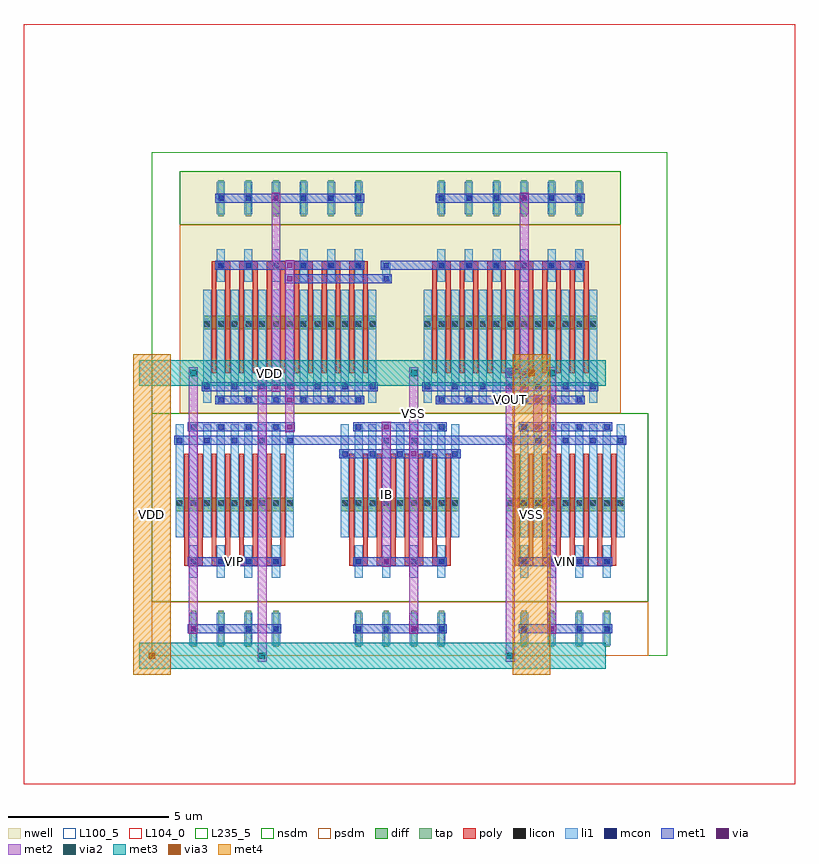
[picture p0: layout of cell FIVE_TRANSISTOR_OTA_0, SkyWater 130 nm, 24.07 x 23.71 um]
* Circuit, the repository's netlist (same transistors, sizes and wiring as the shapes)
* NGSPICE file created from FIVE_TRANSISTOR_OTA_0.ext - technology: sky130A

.subckt PMOS_S_21674997_X6_Y1_1774868989 a_200_252# w_0_0# a_230_525#
X0 w_0_0# a_200_252# a_230_525# w_0_0# sky130_fd_pr__pfet_01v8 ad=0.1113 pd=1.37 as=0.0588 ps=0.7 w=0.42 l=0.15 M=12
.ends

.subckt DCL_PMOS_S_80097108_X6_Y1_1774868987 a_200_252# w_0_0#
X0 w_0_0# a_200_252# a_200_252# w_0_0# sky130_fd_pr__pfet_01v8 ad=0.1113 pd=1.37 as=0.0588 ps=0.7 w=0.42 l=0.15 M=12
.ends

.subckt NMOS_4T_66219913_X4_Y1_1774868988 a_147_525# a_200_252# a_241_1232# a_230_525#
X0 a_230_525# a_200_252# a_147_525# a_241_1232# sky130_fd_pr__nfet_01v8 ad=0.0588 pd=0.7 as=0.0588 ps=0.7 w=0.42 l=0.15 M=8
.ends

.subckt SCM_NMOS_79747830_X2_Y1_1774868990 a_402_525# a_147_525# a_200_252#
X0 a_402_525# a_200_252# a_147_525# a_147_525# sky130_fd_pr__nfet_01v8 ad=0.0588 pd=0.7 as=0.0588 ps=0.7 w=0.42 l=0.15 M=4
X1 a_200_252# a_200_252# a_147_525# a_147_525# sky130_fd_pr__nfet_01v8 ad=0.0588 pd=0.7 as=0.0588 ps=0.7 w=0.42 l=0.15 M=4
.ends

.subckt FIVE_TRANSISTOR_OTA_0 IB VOUT VIP VIN VSS VDD
XPMOS_S_21674997_X6_Y1_1774868989_0 m1_774_1400# VDD VOUT PMOS_S_21674997_X6_Y1_1774868989
XDCL_PMOS_S_80097108_X6_Y1_1774868987_0 m1_774_1400# VDD DCL_PMOS_S_80097108_X6_Y1_1774868987
XNMOS_4T_66219913_X4_Y1_1774868988_0 m1_860_1316# VIN VSS VOUT NMOS_4T_66219913_X4_Y1_1774868988
XNMOS_4T_66219913_X4_Y1_1774868988_1 m1_860_1316# VIP VSS m1_774_1400# NMOS_4T_66219913_X4_Y1_1774868988
XSCM_NMOS_79747830_X2_Y1_1774868990_0 m1_860_1316# VSS IB SCM_NMOS_79747830_X2_Y1_1774868990
.ends

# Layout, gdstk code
from math import pi, radians
import gdstk
lib = gdstk.Library(unit=1e-6, precision=1e-09)
def R(c, l, rs):  # rectangles x0, y0, x1, y1
    for r in rs: c.add(gdstk.rectangle(r[:2], r[2:], *l))
def A(c, l, x, y, w, h, nx, ny, dx, dy):  # array of equal rectangles
    R(c, l, [(x+i*dx, y+j*dy, x+i*dx+w, y+j*dy+h) for i in range(nx) for j in range(ny)])
def P(c, l, *ps):  # polygons
    for p in ps: c.add(gdstk.Polygon(p, *l))
nwell = (64, 20)
diff = (65, 20)
tap = (65, 44)
poly = (66, 20)
licon = (66, 44)
li1 = (67, 20)
mcon = (67, 44)
met1 = (68, 20)
via = (68, 44)
met2 = (69, 20)
via2 = (69, 44)
met3 = (70, 20)
via3 = (70, 44)
met4 = (71, 20)
nsdm = (93, 44)
psdm = (94, 20)
L100_5 = (100, 5)
L104_0 = (104, 0)
L235_5 = (235, 5)

scm_nmos_79747830_x2_y1_ = lib.new_cell('SCM_NMOS_79747830_X2_Y1_1774868990')
R(scm_nmos_79747830_x2_y1_, diff, [(0.735,2.625,4.425,3.045)])
A(scm_nmos_79747830_x2_y1_, tap, 1.205, 6.16, 0.17, 1.12, 4, 1, 0.86, 0)
A(scm_nmos_79747830_x2_y1_, poly, 1, 1.26, 0.15, 3.36, 8, 1, 0.43, 0)
A(scm_nmos_79747830_x2_y1_, poly, 1, 4.485, 0.58, 0.27, 4, 1, 0.86, 0)
A(scm_nmos_79747830_x2_y1_, licon, 0.775, 2.705, 0.17, 0.17, 3, 1, 0.43, 0)
A(scm_nmos_79747830_x2_y1_, licon, 1.635, 2.705, 0.17, 0.17, 3, 1, 0.43, 0)
A(scm_nmos_79747830_x2_y1_, licon, 2.495, 2.705, 0.17, 0.17, 3, 1, 0.43, 0)
A(scm_nmos_79747830_x2_y1_, licon, 3.355, 2.705, 0.17, 0.17, 3, 1, 0.43, 0)
A(scm_nmos_79747830_x2_y1_, licon, 1.205, 4.535, 0.17, 0.17, 4, 2, 0.86, 2.1)
A(scm_nmos_79747830_x2_y1_, li1, 0.735, 0.335, 0.25, 3.53, 9, 1, 0.43, 0)
A(scm_nmos_79747830_x2_y1_, li1, 1.165, 4.115, 0.25, 1.01, 4, 2, 0.86, 2.1)
A(scm_nmos_79747830_x2_y1_, mcon, 0.775, 1.175, 0.17, 0.17, 5, 1, 0.86, 0)
A(scm_nmos_79747830_x2_y1_, mcon, 1.205, 4.535, 0.17, 0.17, 4, 2, 0.86, 2.1)
R(scm_nmos_79747830_x2_y1_, mcon, [(1.205,0.335,1.375,0.505), (3.785,0.335,3.955,0.505), (2.065,0.755,2.235,0.925), (2.925,0.755,3.095,0.925)])
R(scm_nmos_79747830_x2_y1_, met1, [(1.12,0.28,4.04,0.56), (1.98,0.7,3.18,0.98), (0.69,1.12,4.47,1.4), (1.12,4.48,4.04,4.76), (1.12,6.58,4.04,6.86)])
R(scm_nmos_79747830_x2_y1_, via, [(2.075,0.345,2.225,0.495), (2.935,1.185,3.085,1.335), (2.075,4.545,2.225,4.695), (2.935,6.645,3.085,6.795)])
R(scm_nmos_79747830_x2_y1_, met2, [(2.01,0.26,2.29,4.78), (2.87,1.1,3.15,6.88)])
R(scm_nmos_79747830_x2_y1_, nsdm, [(0,0,5.16,5.88)])
R(scm_nmos_79747830_x2_y1_, psdm, [(0,5.88,5.16,7.56)])
R(scm_nmos_79747830_x2_y1_, L100_5, [(0,0,5.16,7.56)])

dcl_pmos_s_80097108_x6_y = lib.new_cell('DCL_PMOS_S_80097108_X6_Y1_1774868987')
R(dcl_pmos_s_80097108_x6_y, nwell, [(0,0,6.88,7.56)])
R(dcl_pmos_s_80097108_x6_y, diff, [(0.735,2.625,6.145,3.045)])
A(dcl_pmos_s_80097108_x6_y, tap, 1.205, 6.16, 0.17, 1.12, 6, 1, 0.86, 0)
A(dcl_pmos_s_80097108_x6_y, poly, 1, 1.26, 0.15, 3.36, 12, 1, 0.43, 0)
A(dcl_pmos_s_80097108_x6_y, poly, 1, 4.485, 0.58, 0.27, 6, 1, 0.86, 0)
A(dcl_pmos_s_80097108_x6_y, licon, 0.775, 2.705, 0.17, 0.17, 3, 1, 0.43, 0)
A(dcl_pmos_s_80097108_x6_y, licon, 1.635, 2.705, 0.17, 0.17, 3, 1, 0.43, 0)
A(dcl_pmos_s_80097108_x6_y, licon, 2.495, 2.705, 0.17, 0.17, 3, 1, 0.43, 0)
A(dcl_pmos_s_80097108_x6_y, licon, 3.355, 2.705, 0.17, 0.17, 3, 1, 0.43, 0)
A(dcl_pmos_s_80097108_x6_y, licon, 4.215, 2.705, 0.17, 0.17, 3, 1, 0.43, 0)
A(dcl_pmos_s_80097108_x6_y, licon, 5.075, 2.705, 0.17, 0.17, 3, 1, 0.43, 0)
A(dcl_pmos_s_80097108_x6_y, licon, 1.205, 4.535, 0.17, 0.17, 6, 2, 0.86, 2.1)
A(dcl_pmos_s_80097108_x6_y, li1, 0.735, 0.335, 0.25, 3.53, 13, 1, 0.43, 0)
A(dcl_pmos_s_80097108_x6_y, li1, 1.165, 4.115, 0.25, 1.01, 6, 2, 0.86, 2.1)
A(dcl_pmos_s_80097108_x6_y, mcon, 1.205, 0.335, 0.17, 0.17, 6, 2, 0.86, 4.2)
A(dcl_pmos_s_80097108_x6_y, mcon, 0.775, 0.755, 0.17, 0.17, 7, 1, 0.86, 0)
A(dcl_pmos_s_80097108_x6_y, mcon, 1.205, 6.635, 0.17, 0.17, 6, 1, 0.86, 0)
R(dcl_pmos_s_80097108_x6_y, met1, [(1.12,0.28,5.76,0.56), (0.69,0.7,6.19,0.98), (1.12,4.48,5.76,4.76), (1.12,6.58,5.76,6.86)])
R(dcl_pmos_s_80097108_x6_y, via, [(3.365,0.345,3.515,0.495), (3.795,0.765,3.945,0.915), (3.365,4.545,3.515,4.695), (3.795,6.645,3.945,6.795)])
R(dcl_pmos_s_80097108_x6_y, met2, [(3.3,0.26,3.58,4.78), (3.73,0.68,4.01,6.88)])
R(dcl_pmos_s_80097108_x6_y, nsdm, [(0,5.88,6.88,7.56)])
R(dcl_pmos_s_80097108_x6_y, psdm, [(0,0,6.88,5.88)])
R(dcl_pmos_s_80097108_x6_y, L100_5, [(0,0,6.88,7.56)])

pmos_s_21674997_x6_y1_17 = lib.new_cell('PMOS_S_21674997_X6_Y1_1774868989')
R(pmos_s_21674997_x6_y1_17, nwell, [(0,0,6.88,7.56)])
R(pmos_s_21674997_x6_y1_17, diff, [(0.735,2.625,6.145,3.045)])
A(pmos_s_21674997_x6_y1_17, tap, 1.205, 6.16, 0.17, 1.12, 6, 1, 0.86, 0)
A(pmos_s_21674997_x6_y1_17, poly, 1, 1.26, 0.15, 3.36, 12, 1, 0.43, 0)
A(pmos_s_21674997_x6_y1_17, poly, 1, 4.485, 0.58, 0.27, 6, 1, 0.86, 0)
A(pmos_s_21674997_x6_y1_17, licon, 0.775, 2.705, 0.17, 0.17, 3, 1, 0.43, 0)
A(pmos_s_21674997_x6_y1_17, licon, 1.635, 2.705, 0.17, 0.17, 3, 1, 0.43, 0)
A(pmos_s_21674997_x6_y1_17, licon, 2.495, 2.705, 0.17, 0.17, 3, 1, 0.43, 0)
A(pmos_s_21674997_x6_y1_17, licon, 3.355, 2.705, 0.17, 0.17, 3, 1, 0.43, 0)
A(pmos_s_21674997_x6_y1_17, licon, 4.215, 2.705, 0.17, 0.17, 3, 1, 0.43, 0)
A(pmos_s_21674997_x6_y1_17, licon, 5.075, 2.705, 0.17, 0.17, 3, 1, 0.43, 0)
A(pmos_s_21674997_x6_y1_17, licon, 1.205, 4.535, 0.17, 0.17, 6, 2, 0.86, 2.1)
A(pmos_s_21674997_x6_y1_17, li1, 0.735, 0.335, 0.25, 3.53, 13, 1, 0.43, 0)
A(pmos_s_21674997_x6_y1_17, li1, 1.165, 4.115, 0.25, 1.01, 6, 2, 0.86, 2.1)
A(pmos_s_21674997_x6_y1_17, mcon, 1.205, 0.335, 0.17, 0.17, 6, 2, 0.86, 4.2)
A(pmos_s_21674997_x6_y1_17, mcon, 0.775, 0.755, 0.17, 0.17, 7, 1, 0.86, 0)
A(pmos_s_21674997_x6_y1_17, mcon, 1.205, 6.635, 0.17, 0.17, 6, 1, 0.86, 0)
R(pmos_s_21674997_x6_y1_17, met1, [(1.12,0.28,5.76,0.56), (0.69,0.7,6.19,0.98), (1.12,4.48,5.76,4.76), (1.12,6.58,5.76,6.86)])
R(pmos_s_21674997_x6_y1_17, via, [(3.795,0.765,3.945,0.915), (3.795,6.645,3.945,6.795)])
R(pmos_s_21674997_x6_y1_17, met2, [(3.73,0.68,4.01,6.88)])
R(pmos_s_21674997_x6_y1_17, nsdm, [(0,5.88,6.88,7.56)])
R(pmos_s_21674997_x6_y1_17, psdm, [(0,0,6.88,5.88)])
R(pmos_s_21674997_x6_y1_17, L100_5, [(0,0,6.88,7.56)])

nmos_4t_66219913_x4_y1_1 = lib.new_cell('NMOS_4T_66219913_X4_Y1_1774868988')
R(nmos_4t_66219913_x4_y1_1, diff, [(0.735,2.625,4.425,3.045)])
A(nmos_4t_66219913_x4_y1_1, tap, 1.205, 6.16, 0.17, 1.12, 4, 1, 0.86, 0)
A(nmos_4t_66219913_x4_y1_1, poly, 1, 1.26, 0.15, 3.36, 8, 1, 0.43, 0)
A(nmos_4t_66219913_x4_y1_1, poly, 1, 4.485, 0.58, 0.27, 4, 1, 0.86, 0)
A(nmos_4t_66219913_x4_y1_1, licon, 0.775, 2.705, 0.17, 0.17, 3, 1, 0.43, 0)
A(nmos_4t_66219913_x4_y1_1, licon, 1.635, 2.705, 0.17, 0.17, 3, 1, 0.43, 0)
A(nmos_4t_66219913_x4_y1_1, licon, 2.495, 2.705, 0.17, 0.17, 3, 1, 0.43, 0)
A(nmos_4t_66219913_x4_y1_1, licon, 3.355, 2.705, 0.17, 0.17, 3, 1, 0.43, 0)
A(nmos_4t_66219913_x4_y1_1, licon, 1.205, 4.535, 0.17, 0.17, 4, 2, 0.86, 2.1)
A(nmos_4t_66219913_x4_y1_1, li1, 0.735, 0.335, 0.25, 3.53, 9, 1, 0.43, 0)
A(nmos_4t_66219913_x4_y1_1, li1, 1.165, 4.115, 0.25, 1.01, 4, 2, 0.86, 2.1)
A(nmos_4t_66219913_x4_y1_1, mcon, 1.205, 0.335, 0.17, 0.17, 4, 2, 0.86, 4.2)
A(nmos_4t_66219913_x4_y1_1, mcon, 0.775, 0.755, 0.17, 0.17, 5, 1, 0.86, 0)
A(nmos_4t_66219913_x4_y1_1, mcon, 1.205, 6.635, 0.17, 0.17, 4, 1, 0.86, 0)
R(nmos_4t_66219913_x4_y1_1, met1, [(1.12,0.28,4.04,0.56), (0.69,0.7,4.47,0.98), (1.12,4.48,4.04,4.76), (1.12,6.58,4.04,6.86)])
R(nmos_4t_66219913_x4_y1_1, nsdm, [(0,0,5.16,5.88)])
R(nmos_4t_66219913_x4_y1_1, psdm, [(0,5.88,5.16,7.56)])
R(nmos_4t_66219913_x4_y1_1, L100_5, [(0,0,5.16,7.56)])

five_transistor_ota_0 = lib.new_cell('FIVE_TRANSISTOR_OTA_0')
R(five_transistor_ota_0, li1, [(7.185,11.675,7.435,11.845), (7.185,11.675,7.435,11.845), (7.185,11.76,7.435,12.18), (7.185,12.095,7.435,12.265), (7.185,12.095,7.435,12.265)])
R(five_transistor_ota_0, mcon, [(7.225,11.675,7.395,11.845), (7.225,11.675,7.395,11.845), (7.225,12.095,7.395,12.265), (7.225,12.095,7.395,12.265)])
R(five_transistor_ota_0, met1, [(1.13,0.7,1.45,0.98), (1.13,0.7,1.45,0.98), (1.13,0.7,1.45,0.98), (12.31,0.7,12.63,0.98), (12.31,0.7,12.63,0.98), (4.3,6.58,7.31,6.86), (8.17,6.58,11.18,6.86), (3.87,7,4.3,7.28), (4.14,7,4.46,7.28), (4.14,7,4.46,7.28), (4.14,7,4.46,7.28), (4.14,7,4.46,7.28), (11.88,7,12.2,7.28), (11.88,7,12.2,7.28), (11.88,7.84,12.2,8.12), (11.88,7.84,12.2,8.12), (3.28,8.68,3.6,8.96), (3.28,8.68,3.6,8.96), (3.28,8.68,3.6,8.96), (3.44,8.68,3.87,8.96), (3.71,8.68,4.03,8.96), (3.71,8.68,4.03,8.96), (3.71,8.68,4.03,8.96), (11.02,8.68,11.34,8.96), (11.02,8.68,11.34,8.96), (11.18,8.68,11.61,8.96), (11.45,8.68,11.77,8.96), (11.45,8.68,11.77,8.96), (4.14,11.62,4.46,11.9), (4.14,11.62,4.46,11.9), (4.3,11.62,7.31,11.9), (7.14,11.62,7.48,11.9), (7.14,11.62,7.48,11.9), (7.14,12.04,7.48,12.32), (7.14,12.04,7.48,12.32), (7.31,12.04,9.03,12.32)])
P(five_transistor_ota_0, met1, [(0,0),(0,0),(0,0),(0,0)],
  [(0,0),(0,0),(0,0),(0,0)],
  [(0,0),(0,0),(0,0),(0,0)],
  [(0,0),(0,0),(0,0),(0,0)],
  [(0,0),(0,0),(0,0),(0,0)],
  [(0,0),(0,0),(0,0),(0,0)],
  [(0,0),(0,0),(0,0),(0,0)],
  [(0,0),(0,0),(0,0),(0,0)],
  [(0,0),(0,0),(0,0),(0,0)],
  [(0,0),(0,0),(0,0),(0,0)],
  [(0,0),(0,0),(0,0),(0,0)],
  [(0,0),(0,0),(0,0),(0,0)],
  [(0,0),(0,0),(0,0),(0,0)],
  [(0,0),(0,0),(0,0),(0,0)])
R(five_transistor_ota_0, via, [(1.215,0.765,1.365,0.915), (1.215,0.765,1.365,0.915), (1.215,0.765,1.365,0.915), (12.395,0.765,12.545,0.915), (12.395,0.765,12.545,0.915), (4.225,7.065,4.375,7.215), (4.225,7.065,4.375,7.215), (4.225,7.065,4.375,7.215), (4.225,7.065,4.375,7.215), (11.965,7.065,12.115,7.215), (11.965,7.065,12.115,7.215), (11.965,7.905,12.115,8.055), (11.965,7.905,12.115,8.055), (3.365,8.745,3.515,8.895), (3.365,8.745,3.515,8.895), (3.365,8.745,3.515,8.895), (3.795,8.745,3.945,8.895), (3.795,8.745,3.945,8.895), (3.795,8.745,3.945,8.895), (11.105,8.745,11.255,8.895), (11.105,8.745,11.255,8.895), (11.535,8.745,11.685,8.895), (11.535,8.745,11.685,8.895), (4.225,11.685,4.375,11.835), (4.225,11.685,4.375,11.835)])
R(five_transistor_ota_0, met2, [(3.3,-0.185,3.58,0.185), (3.3,-0.185,3.58,0.185), (3.3,-0.185,3.58,0.185), (11.04,-0.185,11.32,0.185), (11.04,-0.185,11.32,0.185), (3.3,0,3.58,8.82), (11.04,0,11.32,8.82), (1.15,0.68,1.43,1), (1.15,0.68,1.43,1), (1.15,0.68,1.43,1), (12.33,0.68,12.61,1), (12.33,0.68,12.61,1), (1.15,0.84,1.43,8.82), (12.33,0.84,12.61,8.82), (8.03,6.3,8.31,8.82), (4.16,6.98,4.44,7.3), (4.16,6.98,4.44,7.3), (4.16,6.98,4.44,7.3), (4.16,6.98,4.44,7.3), (11.9,6.98,12.18,7.3), (11.9,6.98,12.18,7.3), (4.16,7.14,4.44,7.98), (11.9,7.14,12.18,7.98), (11.9,7.82,12.18,8.14), (11.9,7.82,12.18,8.14), (1.15,8.635,1.43,9.005), (1.15,8.635,1.43,9.005), (1.15,8.635,1.43,9.005), (8.03,8.635,8.31,9.005), (8.03,8.635,8.31,9.005), (8.03,8.635,8.31,9.005), (8.03,8.635,8.31,9.005), (12.33,8.635,12.61,9.005), (12.33,8.635,12.61,9.005), (3.3,8.66,3.58,8.98), (3.3,8.66,3.58,8.98), (3.3,8.66,3.58,8.98), (3.73,8.66,4.01,8.98), (3.73,8.66,4.01,8.98), (3.73,8.66,4.01,8.98), (11.04,8.66,11.32,8.98), (11.04,8.66,11.32,8.98), (11.47,8.66,11.75,8.98), (11.47,8.66,11.75,8.98), (4.16,11.6,4.44,11.92), (4.16,11.6,4.44,11.92)])
P(five_transistor_ota_0, met2, [(0,0),(0,0),(0,0),(0,0)],
  [(0,0),(0,0),(0,0),(0,0)],
  [(0,0),(0,0),(0,0),(0,0)],
  [(0,0),(0,0),(0,0),(0,0)],
  [(0,0),(0,0),(0,0),(0,0)],
  [(0,0),(0,0),(0,0),(0,0)])
R(five_transistor_ota_0, via2, [(3.34,-0.1,3.54,0.1), (3.34,-0.1,3.54,0.1), (3.34,-0.1,3.54,0.1), (11.08,-0.1,11.28,0.1), (11.08,-0.1,11.28,0.1), (1.19,8.72,1.39,8.92), (1.19,8.72,1.39,8.92), (1.19,8.72,1.39,8.92), (8.07,8.72,8.27,8.92), (8.07,8.72,8.27,8.92), (8.07,8.72,8.27,8.92), (8.07,8.72,8.27,8.92), (12.37,8.72,12.57,8.92), (12.37,8.72,12.57,8.92)])
A(five_transistor_ota_0, met3, -0.4, -0.4, 4.24, 0.8, 3, 2, 3.44, 8.82)
R(five_transistor_ota_0, met3, [(-0.165,-0.4,0.165,0.4), (3.275,-0.4,3.605,0.4), (3.275,-0.4,3.605,0.4), (3.275,-0.4,3.605,0.4), (9.92,-0.4,12.24,0.4), (11.015,-0.4,11.345,0.4), (11.015,-0.4,11.345,0.4), (11.44,-0.4,14.16,0.4), (1.125,8.42,1.455,9.22), (1.125,8.42,1.455,9.22), (1.125,8.42,1.455,9.22), (8.005,8.42,8.335,9.22), (8.005,8.42,8.335,9.22), (8.005,8.42,8.335,9.22), (8.005,8.42,8.335,9.22), (9.92,8.42,12.24,9.22), (11.44,8.42,14.16,9.22), (11.675,8.42,12.005,9.22), (12.305,8.42,12.635,9.22), (12.305,8.42,12.635,9.22)])
R(five_transistor_ota_0, via3, [(-0.1,-0.1,0.1,0.1), (11.74,8.72,11.94,8.92)])
R(five_transistor_ota_0, met4, [(-0.59,-0.59,0.59,9.41), (11.25,-0.59,12.43,9.41), (-0.59,-0.165,0.59,0.165), (11.25,8.655,12.43,8.985)])
R(five_transistor_ota_0, L104_0, [(-4,-4,20.07,19.71)])
R(five_transistor_ota_0, L235_5, [(0,0,16.07,15.71)])
five_transistor_ota_0.add(gdstk.Reference(scm_nmos_79747830_x2_y1_, (5.16,7.56), x_reflection=True))
five_transistor_ota_0.add(gdstk.Reference(dcl_pmos_s_80097108_x6_y, (7.74,7.56), rotation=pi, x_reflection=True))
five_transistor_ota_0.add(gdstk.Reference(pmos_s_21674997_x6_y1_17, (7.74,7.56)))
five_transistor_ota_0.add(gdstk.Reference(nmos_4t_66219913_x4_y1_1, (5.16,7.56), rotation=pi))
five_transistor_ota_0.add(gdstk.Reference(nmos_4t_66219913_x4_y1_1, (10.32,7.56), x_reflection=True))
five_transistor_ota_0.add(gdstk.Label('IB', (7.31,5.04), layer=69, texttype=5))
five_transistor_ota_0.add(gdstk.Label('VOUT', (11.18,7.98), layer=68, texttype=5))
five_transistor_ota_0.add(gdstk.Label('VIP', (2.58,2.94), layer=68, texttype=5))
five_transistor_ota_0.add(gdstk.Label('VIN', (12.9,2.94), layer=68, texttype=5))
five_transistor_ota_0.add(gdstk.Label('VSS', (8.17,7.56), layer=69, texttype=5))
five_transistor_ota_0.add(gdstk.Label('VSS', (11.84,4.41), layer=71, texttype=5))
five_transistor_ota_0.add(gdstk.Label('VSS', (11.84,4.41), layer=71, texttype=5))
five_transistor_ota_0.add(gdstk.Label('VSS', (11.84,4.41), layer=71, texttype=5))
five_transistor_ota_0.add(gdstk.Label('VSS', (11.84,4.41), layer=71, texttype=5))
five_transistor_ota_0.add(gdstk.Label('VSS', (11.84,4.41), layer=71, texttype=5))
five_transistor_ota_0.add(gdstk.Label('VSS', (11.84,4.41), layer=71, texttype=5))
five_transistor_ota_0.add(gdstk.Label('VSS', (11.84,4.41), layer=71, texttype=5))
five_transistor_ota_0.add(gdstk.Label('VSS', (11.84,4.41), layer=71, texttype=5))
five_transistor_ota_0.add(gdstk.Label('VDD', (0,4.41), layer=71, texttype=5))
five_transistor_ota_0.add(gdstk.Label('VDD', (3.655,8.82), layer=68, texttype=5))
five_transistor_ota_0.add(gdstk.Label('VDD', (0,4.41), layer=71, texttype=5))
five_transistor_ota_0.add(gdstk.Label('VDD', (0,4.41), layer=71, texttype=5))
five_transistor_ota_0.add(gdstk.Label('VDD', (0,4.41), layer=71, texttype=5))
five_transistor_ota_0.add(gdstk.Label('VDD', (0,4.41), layer=71, texttype=5))
five_transistor_ota_0.add(gdstk.Label('VDD', (0,4.41), layer=71, texttype=5))
five_transistor_ota_0.add(gdstk.Label('VDD', (0,4.41), layer=71, texttype=5))
five_transistor_ota_0.add(gdstk.Label('VDD', (0,4.41), layer=71, texttype=5))

lib.write_gds('FIVE_TRANSISTOR_OTA_0.gds')
